VERSION 5.7 ;
BUSBITCHARS "[]" ;
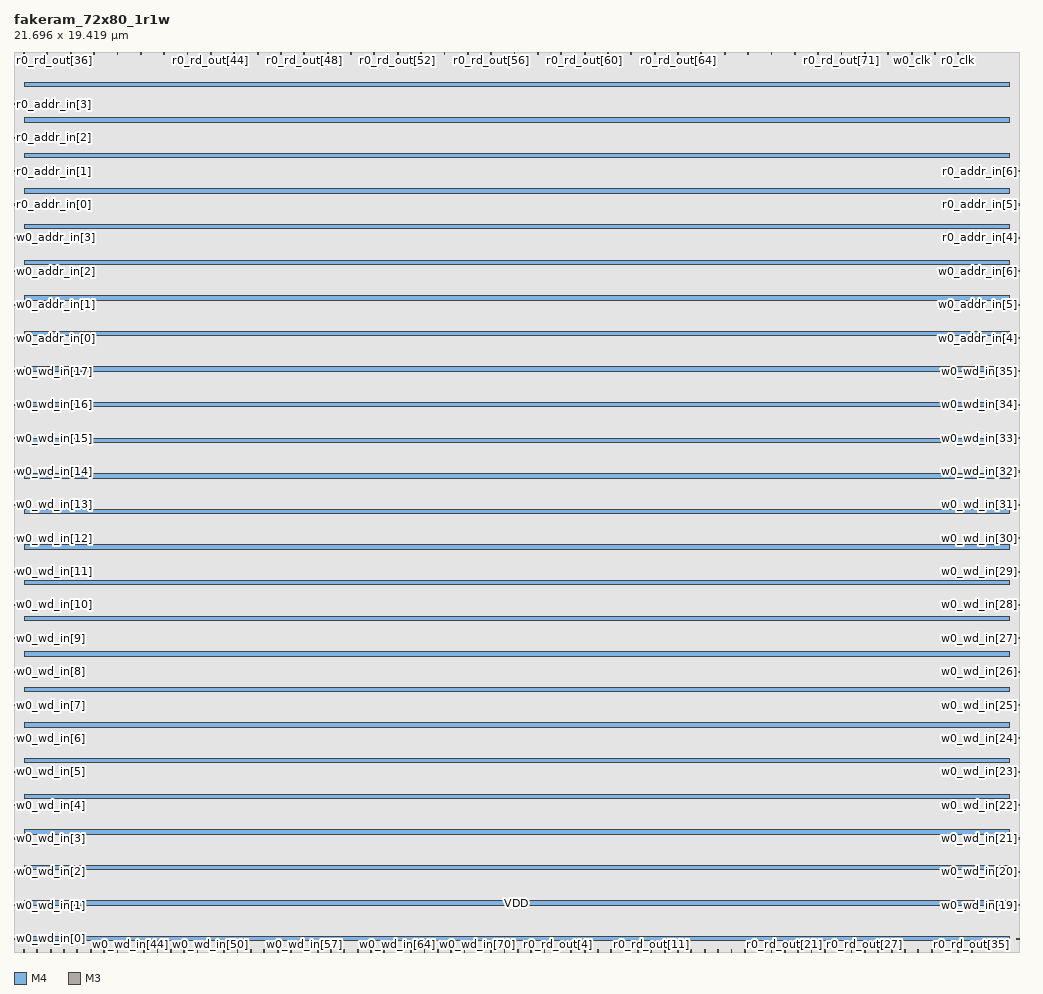
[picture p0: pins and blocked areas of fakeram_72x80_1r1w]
MACRO fakeram_72x80_1r1w
  FOREIGN fakeram_72x80_1r1w 0 0 ;
  SYMMETRY X Y R90 ;
  SIZE 21.696 BY 19.419 ;
  CLASS BLOCK ;
  PIN w0_wd_in[0]
    DIRECTION INPUT ;
    USE SIGNAL ;
    SHAPE ABUTMENT ;
    PORT
      LAYER M4 ;
      RECT 0.000 0.276 0.072 0.300 ;
    END
  END w0_wd_in[0]
  PIN w0_wd_in[1]
    DIRECTION INPUT ;
    USE SIGNAL ;
    SHAPE ABUTMENT ;
    PORT
      LAYER M4 ;
      RECT 0.000 0.996 0.072 1.020 ;
    END
  END w0_wd_in[1]
  PIN w0_wd_in[2]
    DIRECTION INPUT ;
    USE SIGNAL ;
    SHAPE ABUTMENT ;
    PORT
      LAYER M4 ;
      RECT 0.000 1.716 0.072 1.740 ;
    END
  END w0_wd_in[2]
  PIN w0_wd_in[3]
    DIRECTION INPUT ;
    USE SIGNAL ;
    SHAPE ABUTMENT ;
    PORT
      LAYER M4 ;
      RECT 0.000 2.436 0.072 2.460 ;
    END
  END w0_wd_in[3]
  PIN w0_wd_in[4]
    DIRECTION INPUT ;
    USE SIGNAL ;
    SHAPE ABUTMENT ;
    PORT
      LAYER M4 ;
      RECT 0.000 3.156 0.072 3.180 ;
    END
  END w0_wd_in[4]
  PIN w0_wd_in[5]
    DIRECTION INPUT ;
    USE SIGNAL ;
    SHAPE ABUTMENT ;
    PORT
      LAYER M4 ;
      RECT 0.000 3.876 0.072 3.900 ;
    END
  END w0_wd_in[5]
  PIN w0_wd_in[6]
    DIRECTION INPUT ;
    USE SIGNAL ;
    SHAPE ABUTMENT ;
    PORT
      LAYER M4 ;
      RECT 0.000 4.596 0.072 4.620 ;
    END
  END w0_wd_in[6]
  PIN w0_wd_in[7]
    DIRECTION INPUT ;
    USE SIGNAL ;
    SHAPE ABUTMENT ;
    PORT
      LAYER M4 ;
      RECT 0.000 5.316 0.072 5.340 ;
    END
  END w0_wd_in[7]
  PIN w0_wd_in[8]
    DIRECTION INPUT ;
    USE SIGNAL ;
    SHAPE ABUTMENT ;
    PORT
      LAYER M4 ;
      RECT 0.000 6.036 0.072 6.060 ;
    END
  END w0_wd_in[8]
  PIN w0_wd_in[9]
    DIRECTION INPUT ;
    USE SIGNAL ;
    SHAPE ABUTMENT ;
    PORT
      LAYER M4 ;
      RECT 0.000 6.756 0.072 6.780 ;
    END
  END w0_wd_in[9]
  PIN w0_wd_in[10]
    DIRECTION INPUT ;
    USE SIGNAL ;
    SHAPE ABUTMENT ;
    PORT
      LAYER M4 ;
      RECT 0.000 7.476 0.072 7.500 ;
    END
  END w0_wd_in[10]
  PIN w0_wd_in[11]
    DIRECTION INPUT ;
    USE SIGNAL ;
    SHAPE ABUTMENT ;
    PORT
      LAYER M4 ;
      RECT 0.000 8.196 0.072 8.220 ;
    END
  END w0_wd_in[11]
  PIN w0_wd_in[12]
    DIRECTION INPUT ;
    USE SIGNAL ;
    SHAPE ABUTMENT ;
    PORT
      LAYER M4 ;
      RECT 0.000 8.916 0.072 8.940 ;
    END
  END w0_wd_in[12]
  PIN w0_wd_in[13]
    DIRECTION INPUT ;
    USE SIGNAL ;
    SHAPE ABUTMENT ;
    PORT
      LAYER M4 ;
      RECT 0.000 9.636 0.072 9.660 ;
    END
  END w0_wd_in[13]
  PIN w0_wd_in[14]
    DIRECTION INPUT ;
    USE SIGNAL ;
    SHAPE ABUTMENT ;
    PORT
      LAYER M4 ;
      RECT 0.000 10.356 0.072 10.380 ;
    END
  END w0_wd_in[14]
  PIN w0_wd_in[15]
    DIRECTION INPUT ;
    USE SIGNAL ;
    SHAPE ABUTMENT ;
    PORT
      LAYER M4 ;
      RECT 0.000 11.076 0.072 11.100 ;
    END
  END w0_wd_in[15]
  PIN w0_wd_in[16]
    DIRECTION INPUT ;
    USE SIGNAL ;
    SHAPE ABUTMENT ;
    PORT
      LAYER M4 ;
      RECT 0.000 11.796 0.072 11.820 ;
    END
  END w0_wd_in[16]
  PIN w0_wd_in[17]
    DIRECTION INPUT ;
    USE SIGNAL ;
    SHAPE ABUTMENT ;
    PORT
      LAYER M4 ;
      RECT 0.000 12.516 0.072 12.540 ;
    END
  END w0_wd_in[17]
  PIN w0_wd_in[18]
    DIRECTION INPUT ;
    USE SIGNAL ;
    SHAPE ABUTMENT ;
    PORT
      LAYER M4 ;
      RECT 21.624 0.276 21.696 0.300 ;
    END
  END w0_wd_in[18]
  PIN w0_wd_in[19]
    DIRECTION INPUT ;
    USE SIGNAL ;
    SHAPE ABUTMENT ;
    PORT
      LAYER M4 ;
      RECT 21.624 0.996 21.696 1.020 ;
    END
  END w0_wd_in[19]
  PIN w0_wd_in[20]
    DIRECTION INPUT ;
    USE SIGNAL ;
    SHAPE ABUTMENT ;
    PORT
      LAYER M4 ;
      RECT 21.624 1.716 21.696 1.740 ;
    END
  END w0_wd_in[20]
  PIN w0_wd_in[21]
    DIRECTION INPUT ;
    USE SIGNAL ;
    SHAPE ABUTMENT ;
    PORT
      LAYER M4 ;
      RECT 21.624 2.436 21.696 2.460 ;
    END
  END w0_wd_in[21]
  PIN w0_wd_in[22]
    DIRECTION INPUT ;
    USE SIGNAL ;
    SHAPE ABUTMENT ;
    PORT
      LAYER M4 ;
      RECT 21.624 3.156 21.696 3.180 ;
    END
  END w0_wd_in[22]
  PIN w0_wd_in[23]
    DIRECTION INPUT ;
    USE SIGNAL ;
    SHAPE ABUTMENT ;
    PORT
      LAYER M4 ;
      RECT 21.624 3.876 21.696 3.900 ;
    END
  END w0_wd_in[23]
  PIN w0_wd_in[24]
    DIRECTION INPUT ;
    USE SIGNAL ;
    SHAPE ABUTMENT ;
    PORT
      LAYER M4 ;
      RECT 21.624 4.596 21.696 4.620 ;
    END
  END w0_wd_in[24]
  PIN w0_wd_in[25]
    DIRECTION INPUT ;
    USE SIGNAL ;
    SHAPE ABUTMENT ;
    PORT
      LAYER M4 ;
      RECT 21.624 5.316 21.696 5.340 ;
    END
  END w0_wd_in[25]
  PIN w0_wd_in[26]
    DIRECTION INPUT ;
    USE SIGNAL ;
    SHAPE ABUTMENT ;
    PORT
      LAYER M4 ;
      RECT 21.624 6.036 21.696 6.060 ;
    END
  END w0_wd_in[26]
  PIN w0_wd_in[27]
    DIRECTION INPUT ;
    USE SIGNAL ;
    SHAPE ABUTMENT ;
    PORT
      LAYER M4 ;
      RECT 21.624 6.756 21.696 6.780 ;
    END
  END w0_wd_in[27]
  PIN w0_wd_in[28]
    DIRECTION INPUT ;
    USE SIGNAL ;
    SHAPE ABUTMENT ;
    PORT
      LAYER M4 ;
      RECT 21.624 7.476 21.696 7.500 ;
    END
  END w0_wd_in[28]
  PIN w0_wd_in[29]
    DIRECTION INPUT ;
    USE SIGNAL ;
    SHAPE ABUTMENT ;
    PORT
      LAYER M4 ;
      RECT 21.624 8.196 21.696 8.220 ;
    END
  END w0_wd_in[29]
  PIN w0_wd_in[30]
    DIRECTION INPUT ;
    USE SIGNAL ;
    SHAPE ABUTMENT ;
    PORT
      LAYER M4 ;
      RECT 21.624 8.916 21.696 8.940 ;
    END
  END w0_wd_in[30]
  PIN w0_wd_in[31]
    DIRECTION INPUT ;
    USE SIGNAL ;
    SHAPE ABUTMENT ;
    PORT
      LAYER M4 ;
      RECT 21.624 9.636 21.696 9.660 ;
    END
  END w0_wd_in[31]
  PIN w0_wd_in[32]
    DIRECTION INPUT ;
    USE SIGNAL ;
    SHAPE ABUTMENT ;
    PORT
      LAYER M4 ;
      RECT 21.624 10.356 21.696 10.380 ;
    END
  END w0_wd_in[32]
  PIN w0_wd_in[33]
    DIRECTION INPUT ;
    USE SIGNAL ;
    SHAPE ABUTMENT ;
    PORT
      LAYER M4 ;
      RECT 21.624 11.076 21.696 11.100 ;
    END
  END w0_wd_in[33]
  PIN w0_wd_in[34]
    DIRECTION INPUT ;
    USE SIGNAL ;
    SHAPE ABUTMENT ;
    PORT
      LAYER M4 ;
      RECT 21.624 11.796 21.696 11.820 ;
    END
  END w0_wd_in[34]
  PIN w0_wd_in[35]
    DIRECTION INPUT ;
    USE SIGNAL ;
    SHAPE ABUTMENT ;
    PORT
      LAYER M4 ;
      RECT 21.624 12.516 21.696 12.540 ;
    END
  END w0_wd_in[35]
  PIN w0_wd_in[36]
    DIRECTION OUTPUT ;
    USE SIGNAL ;
    SHAPE ABUTMENT ;
    PORT
      LAYER M3 ;
      RECT 0.207 0.000 0.225 0.054 ;
    END
  END w0_wd_in[36]
  PIN w0_wd_in[37]
    DIRECTION OUTPUT ;
    USE SIGNAL ;
    SHAPE ABUTMENT ;
    PORT
      LAYER M3 ;
      RECT 0.495 0.000 0.513 0.054 ;
    END
  END w0_wd_in[37]
  PIN w0_wd_in[38]
    DIRECTION OUTPUT ;
    USE SIGNAL ;
    SHAPE ABUTMENT ;
    PORT
      LAYER M3 ;
      RECT 0.783 0.000 0.801 0.054 ;
    END
  END w0_wd_in[38]
  PIN w0_wd_in[39]
    DIRECTION OUTPUT ;
    USE SIGNAL ;
    SHAPE ABUTMENT ;
    PORT
      LAYER M3 ;
      RECT 1.071 0.000 1.089 0.054 ;
    END
  END w0_wd_in[39]
  PIN w0_wd_in[40]
    DIRECTION OUTPUT ;
    USE SIGNAL ;
    SHAPE ABUTMENT ;
    PORT
      LAYER M3 ;
      RECT 1.359 0.000 1.377 0.054 ;
    END
  END w0_wd_in[40]
  PIN w0_wd_in[41]
    DIRECTION OUTPUT ;
    USE SIGNAL ;
    SHAPE ABUTMENT ;
    PORT
      LAYER M3 ;
      RECT 1.647 0.000 1.665 0.054 ;
    END
  END w0_wd_in[41]
  PIN w0_wd_in[42]
    DIRECTION OUTPUT ;
    USE SIGNAL ;
    SHAPE ABUTMENT ;
    PORT
      LAYER M3 ;
      RECT 1.935 0.000 1.953 0.054 ;
    END
  END w0_wd_in[42]
  PIN w0_wd_in[43]
    DIRECTION OUTPUT ;
    USE SIGNAL ;
    SHAPE ABUTMENT ;
    PORT
      LAYER M3 ;
      RECT 2.223 0.000 2.241 0.054 ;
    END
  END w0_wd_in[43]
  PIN w0_wd_in[44]
    DIRECTION OUTPUT ;
    USE SIGNAL ;
    SHAPE ABUTMENT ;
    PORT
      LAYER M3 ;
      RECT 2.511 0.000 2.529 0.054 ;
    END
  END w0_wd_in[44]
  PIN w0_wd_in[45]
    DIRECTION OUTPUT ;
    USE SIGNAL ;
    SHAPE ABUTMENT ;
    PORT
      LAYER M3 ;
      RECT 2.799 0.000 2.817 0.054 ;
    END
  END w0_wd_in[45]
  PIN w0_wd_in[46]
    DIRECTION OUTPUT ;
    USE SIGNAL ;
    SHAPE ABUTMENT ;
    PORT
      LAYER M3 ;
      RECT 3.087 0.000 3.105 0.054 ;
    END
  END w0_wd_in[46]
  PIN w0_wd_in[47]
    DIRECTION OUTPUT ;
    USE SIGNAL ;
    SHAPE ABUTMENT ;
    PORT
      LAYER M3 ;
      RECT 3.375 0.000 3.393 0.054 ;
    END
  END w0_wd_in[47]
  PIN w0_wd_in[48]
    DIRECTION OUTPUT ;
    USE SIGNAL ;
    SHAPE ABUTMENT ;
    PORT
      LAYER M3 ;
      RECT 3.663 0.000 3.681 0.054 ;
    END
  END w0_wd_in[48]
  PIN w0_wd_in[49]
    DIRECTION OUTPUT ;
    USE SIGNAL ;
    SHAPE ABUTMENT ;
    PORT
      LAYER M3 ;
      RECT 3.951 0.000 3.969 0.054 ;
    END
  END w0_wd_in[49]
  PIN w0_wd_in[50]
    DIRECTION OUTPUT ;
    USE SIGNAL ;
    SHAPE ABUTMENT ;
    PORT
      LAYER M3 ;
      RECT 4.239 0.000 4.257 0.054 ;
    END
  END w0_wd_in[50]
  PIN w0_wd_in[51]
    DIRECTION OUTPUT ;
    USE SIGNAL ;
    SHAPE ABUTMENT ;
    PORT
      LAYER M3 ;
      RECT 4.527 0.000 4.545 0.054 ;
    END
  END w0_wd_in[51]
  PIN w0_wd_in[52]
    DIRECTION OUTPUT ;
    USE SIGNAL ;
    SHAPE ABUTMENT ;
    PORT
      LAYER M3 ;
      RECT 4.815 0.000 4.833 0.054 ;
    END
  END w0_wd_in[52]
  PIN w0_wd_in[53]
    DIRECTION OUTPUT ;
    USE SIGNAL ;
    SHAPE ABUTMENT ;
    PORT
      LAYER M3 ;
      RECT 5.103 0.000 5.121 0.054 ;
    END
  END w0_wd_in[53]
  PIN w0_wd_in[54]
    DIRECTION OUTPUT ;
    USE SIGNAL ;
    SHAPE ABUTMENT ;
    PORT
      LAYER M3 ;
      RECT 5.391 0.000 5.409 0.054 ;
    END
  END w0_wd_in[54]
  PIN w0_wd_in[55]
    DIRECTION OUTPUT ;
    USE SIGNAL ;
    SHAPE ABUTMENT ;
    PORT
      LAYER M3 ;
      RECT 5.679 0.000 5.697 0.054 ;
    END
  END w0_wd_in[55]
  PIN w0_wd_in[56]
    DIRECTION OUTPUT ;
    USE SIGNAL ;
    SHAPE ABUTMENT ;
    PORT
      LAYER M3 ;
      RECT 5.967 0.000 5.985 0.054 ;
    END
  END w0_wd_in[56]
  PIN w0_wd_in[57]
    DIRECTION OUTPUT ;
    USE SIGNAL ;
    SHAPE ABUTMENT ;
    PORT
      LAYER M3 ;
      RECT 6.255 0.000 6.273 0.054 ;
    END
  END w0_wd_in[57]
  PIN w0_wd_in[58]
    DIRECTION OUTPUT ;
    USE SIGNAL ;
    SHAPE ABUTMENT ;
    PORT
      LAYER M3 ;
      RECT 6.543 0.000 6.561 0.054 ;
    END
  END w0_wd_in[58]
  PIN w0_wd_in[59]
    DIRECTION OUTPUT ;
    USE SIGNAL ;
    SHAPE ABUTMENT ;
    PORT
      LAYER M3 ;
      RECT 6.831 0.000 6.849 0.054 ;
    END
  END w0_wd_in[59]
  PIN w0_wd_in[60]
    DIRECTION OUTPUT ;
    USE SIGNAL ;
    SHAPE ABUTMENT ;
    PORT
      LAYER M3 ;
      RECT 7.119 0.000 7.137 0.054 ;
    END
  END w0_wd_in[60]
  PIN w0_wd_in[61]
    DIRECTION OUTPUT ;
    USE SIGNAL ;
    SHAPE ABUTMENT ;
    PORT
      LAYER M3 ;
      RECT 7.407 0.000 7.425 0.054 ;
    END
  END w0_wd_in[61]
  PIN w0_wd_in[62]
    DIRECTION OUTPUT ;
    USE SIGNAL ;
    SHAPE ABUTMENT ;
    PORT
      LAYER M3 ;
      RECT 7.695 0.000 7.713 0.054 ;
    END
  END w0_wd_in[62]
  PIN w0_wd_in[63]
    DIRECTION OUTPUT ;
    USE SIGNAL ;
    SHAPE ABUTMENT ;
    PORT
      LAYER M3 ;
      RECT 7.983 0.000 8.001 0.054 ;
    END
  END w0_wd_in[63]
  PIN w0_wd_in[64]
    DIRECTION OUTPUT ;
    USE SIGNAL ;
    SHAPE ABUTMENT ;
    PORT
      LAYER M3 ;
      RECT 8.271 0.000 8.289 0.054 ;
    END
  END w0_wd_in[64]
  PIN w0_wd_in[65]
    DIRECTION OUTPUT ;
    USE SIGNAL ;
    SHAPE ABUTMENT ;
    PORT
      LAYER M3 ;
      RECT 8.559 0.000 8.577 0.054 ;
    END
  END w0_wd_in[65]
  PIN w0_wd_in[66]
    DIRECTION OUTPUT ;
    USE SIGNAL ;
    SHAPE ABUTMENT ;
    PORT
      LAYER M3 ;
      RECT 8.847 0.000 8.865 0.054 ;
    END
  END w0_wd_in[66]
  PIN w0_wd_in[67]
    DIRECTION OUTPUT ;
    USE SIGNAL ;
    SHAPE ABUTMENT ;
    PORT
      LAYER M3 ;
      RECT 9.135 0.000 9.153 0.054 ;
    END
  END w0_wd_in[67]
  PIN w0_wd_in[68]
    DIRECTION OUTPUT ;
    USE SIGNAL ;
    SHAPE ABUTMENT ;
    PORT
      LAYER M3 ;
      RECT 9.423 0.000 9.441 0.054 ;
    END
  END w0_wd_in[68]
  PIN w0_wd_in[69]
    DIRECTION OUTPUT ;
    USE SIGNAL ;
    SHAPE ABUTMENT ;
    PORT
      LAYER M3 ;
      RECT 9.711 0.000 9.729 0.054 ;
    END
  END w0_wd_in[69]
  PIN w0_wd_in[70]
    DIRECTION OUTPUT ;
    USE SIGNAL ;
    SHAPE ABUTMENT ;
    PORT
      LAYER M3 ;
      RECT 9.999 0.000 10.017 0.054 ;
    END
  END w0_wd_in[70]
  PIN w0_wd_in[71]
    DIRECTION OUTPUT ;
    USE SIGNAL ;
    SHAPE ABUTMENT ;
    PORT
      LAYER M3 ;
      RECT 10.287 0.000 10.305 0.054 ;
    END
  END w0_wd_in[71]
  PIN r0_rd_out[0]
    DIRECTION OUTPUT ;
    USE SIGNAL ;
    SHAPE ABUTMENT ;
    PORT
      LAYER M3 ;
      RECT 10.575 0.000 10.593 0.054 ;
    END
  END r0_rd_out[0]
  PIN r0_rd_out[1]
    DIRECTION OUTPUT ;
    USE SIGNAL ;
    SHAPE ABUTMENT ;
    PORT
      LAYER M3 ;
      RECT 10.863 0.000 10.881 0.054 ;
    END
  END r0_rd_out[1]
  PIN r0_rd_out[2]
    DIRECTION OUTPUT ;
    USE SIGNAL ;
    SHAPE ABUTMENT ;
    PORT
      LAYER M3 ;
      RECT 11.151 0.000 11.169 0.054 ;
    END
  END r0_rd_out[2]
  PIN r0_rd_out[3]
    DIRECTION OUTPUT ;
    USE SIGNAL ;
    SHAPE ABUTMENT ;
    PORT
      LAYER M3 ;
      RECT 11.439 0.000 11.457 0.054 ;
    END
  END r0_rd_out[3]
  PIN r0_rd_out[4]
    DIRECTION OUTPUT ;
    USE SIGNAL ;
    SHAPE ABUTMENT ;
    PORT
      LAYER M3 ;
      RECT 11.727 0.000 11.745 0.054 ;
    END
  END r0_rd_out[4]
  PIN r0_rd_out[5]
    DIRECTION OUTPUT ;
    USE SIGNAL ;
    SHAPE ABUTMENT ;
    PORT
      LAYER M3 ;
      RECT 12.015 0.000 12.033 0.054 ;
    END
  END r0_rd_out[5]
  PIN r0_rd_out[6]
    DIRECTION OUTPUT ;
    USE SIGNAL ;
    SHAPE ABUTMENT ;
    PORT
      LAYER M3 ;
      RECT 12.303 0.000 12.321 0.054 ;
    END
  END r0_rd_out[6]
  PIN r0_rd_out[7]
    DIRECTION OUTPUT ;
    USE SIGNAL ;
    SHAPE ABUTMENT ;
    PORT
      LAYER M3 ;
      RECT 12.591 0.000 12.609 0.054 ;
    END
  END r0_rd_out[7]
  PIN r0_rd_out[8]
    DIRECTION OUTPUT ;
    USE SIGNAL ;
    SHAPE ABUTMENT ;
    PORT
      LAYER M3 ;
      RECT 12.879 0.000 12.897 0.054 ;
    END
  END r0_rd_out[8]
  PIN r0_rd_out[9]
    DIRECTION OUTPUT ;
    USE SIGNAL ;
    SHAPE ABUTMENT ;
    PORT
      LAYER M3 ;
      RECT 13.167 0.000 13.185 0.054 ;
    END
  END r0_rd_out[9]
  PIN r0_rd_out[10]
    DIRECTION OUTPUT ;
    USE SIGNAL ;
    SHAPE ABUTMENT ;
    PORT
      LAYER M3 ;
      RECT 13.455 0.000 13.473 0.054 ;
    END
  END r0_rd_out[10]
  PIN r0_rd_out[11]
    DIRECTION OUTPUT ;
    USE SIGNAL ;
    SHAPE ABUTMENT ;
    PORT
      LAYER M3 ;
      RECT 13.743 0.000 13.761 0.054 ;
    END
  END r0_rd_out[11]
  PIN r0_rd_out[12]
    DIRECTION OUTPUT ;
    USE SIGNAL ;
    SHAPE ABUTMENT ;
    PORT
      LAYER M3 ;
      RECT 14.031 0.000 14.049 0.054 ;
    END
  END r0_rd_out[12]
  PIN r0_rd_out[13]
    DIRECTION OUTPUT ;
    USE SIGNAL ;
    SHAPE ABUTMENT ;
    PORT
      LAYER M3 ;
      RECT 14.319 0.000 14.337 0.054 ;
    END
  END r0_rd_out[13]
  PIN r0_rd_out[14]
    DIRECTION OUTPUT ;
    USE SIGNAL ;
    SHAPE ABUTMENT ;
    PORT
      LAYER M3 ;
      RECT 14.607 0.000 14.625 0.054 ;
    END
  END r0_rd_out[14]
  PIN r0_rd_out[15]
    DIRECTION OUTPUT ;
    USE SIGNAL ;
    SHAPE ABUTMENT ;
    PORT
      LAYER M3 ;
      RECT 14.895 0.000 14.913 0.054 ;
    END
  END r0_rd_out[15]
  PIN r0_rd_out[16]
    DIRECTION OUTPUT ;
    USE SIGNAL ;
    SHAPE ABUTMENT ;
    PORT
      LAYER M3 ;
      RECT 15.183 0.000 15.201 0.054 ;
    END
  END r0_rd_out[16]
  PIN r0_rd_out[17]
    DIRECTION OUTPUT ;
    USE SIGNAL ;
    SHAPE ABUTMENT ;
    PORT
      LAYER M3 ;
      RECT 15.471 0.000 15.489 0.054 ;
    END
  END r0_rd_out[17]
  PIN r0_rd_out[18]
    DIRECTION OUTPUT ;
    USE SIGNAL ;
    SHAPE ABUTMENT ;
    PORT
      LAYER M3 ;
      RECT 15.759 0.000 15.777 0.054 ;
    END
  END r0_rd_out[18]
  PIN r0_rd_out[19]
    DIRECTION OUTPUT ;
    USE SIGNAL ;
    SHAPE ABUTMENT ;
    PORT
      LAYER M3 ;
      RECT 16.047 0.000 16.065 0.054 ;
    END
  END r0_rd_out[19]
  PIN r0_rd_out[20]
    DIRECTION OUTPUT ;
    USE SIGNAL ;
    SHAPE ABUTMENT ;
    PORT
      LAYER M3 ;
      RECT 16.335 0.000 16.353 0.054 ;
    END
  END r0_rd_out[20]
  PIN r0_rd_out[21]
    DIRECTION OUTPUT ;
    USE SIGNAL ;
    SHAPE ABUTMENT ;
    PORT
      LAYER M3 ;
      RECT 16.623 0.000 16.641 0.054 ;
    END
  END r0_rd_out[21]
  PIN r0_rd_out[22]
    DIRECTION OUTPUT ;
    USE SIGNAL ;
    SHAPE ABUTMENT ;
    PORT
      LAYER M3 ;
      RECT 16.911 0.000 16.929 0.054 ;
    END
  END r0_rd_out[22]
  PIN r0_rd_out[23]
    DIRECTION OUTPUT ;
    USE SIGNAL ;
    SHAPE ABUTMENT ;
    PORT
      LAYER M3 ;
      RECT 17.199 0.000 17.217 0.054 ;
    END
  END r0_rd_out[23]
  PIN r0_rd_out[24]
    DIRECTION OUTPUT ;
    USE SIGNAL ;
    SHAPE ABUTMENT ;
    PORT
      LAYER M3 ;
      RECT 17.487 0.000 17.505 0.054 ;
    END
  END r0_rd_out[24]
  PIN r0_rd_out[25]
    DIRECTION OUTPUT ;
    USE SIGNAL ;
    SHAPE ABUTMENT ;
    PORT
      LAYER M3 ;
      RECT 17.775 0.000 17.793 0.054 ;
    END
  END r0_rd_out[25]
  PIN r0_rd_out[26]
    DIRECTION OUTPUT ;
    USE SIGNAL ;
    SHAPE ABUTMENT ;
    PORT
      LAYER M3 ;
      RECT 18.063 0.000 18.081 0.054 ;
    END
  END r0_rd_out[26]
  PIN r0_rd_out[27]
    DIRECTION OUTPUT ;
    USE SIGNAL ;
    SHAPE ABUTMENT ;
    PORT
      LAYER M3 ;
      RECT 18.351 0.000 18.369 0.054 ;
    END
  END r0_rd_out[27]
  PIN r0_rd_out[28]
    DIRECTION OUTPUT ;
    USE SIGNAL ;
    SHAPE ABUTMENT ;
    PORT
      LAYER M3 ;
      RECT 18.639 0.000 18.657 0.054 ;
    END
  END r0_rd_out[28]
  PIN r0_rd_out[29]
    DIRECTION OUTPUT ;
    USE SIGNAL ;
    SHAPE ABUTMENT ;
    PORT
      LAYER M3 ;
      RECT 18.927 0.000 18.945 0.054 ;
    END
  END r0_rd_out[29]
  PIN r0_rd_out[30]
    DIRECTION OUTPUT ;
    USE SIGNAL ;
    SHAPE ABUTMENT ;
    PORT
      LAYER M3 ;
      RECT 19.215 0.000 19.233 0.054 ;
    END
  END r0_rd_out[30]
  PIN r0_rd_out[31]
    DIRECTION OUTPUT ;
    USE SIGNAL ;
    SHAPE ABUTMENT ;
    PORT
      LAYER M3 ;
      RECT 19.503 0.000 19.521 0.054 ;
    END
  END r0_rd_out[31]
  PIN r0_rd_out[32]
    DIRECTION OUTPUT ;
    USE SIGNAL ;
    SHAPE ABUTMENT ;
    PORT
      LAYER M3 ;
      RECT 19.791 0.000 19.809 0.054 ;
    END
  END r0_rd_out[32]
  PIN r0_rd_out[33]
    DIRECTION OUTPUT ;
    USE SIGNAL ;
    SHAPE ABUTMENT ;
    PORT
      LAYER M3 ;
      RECT 20.079 0.000 20.097 0.054 ;
    END
  END r0_rd_out[33]
  PIN r0_rd_out[34]
    DIRECTION OUTPUT ;
    USE SIGNAL ;
    SHAPE ABUTMENT ;
    PORT
      LAYER M3 ;
      RECT 20.367 0.000 20.385 0.054 ;
    END
  END r0_rd_out[34]
  PIN r0_rd_out[35]
    DIRECTION OUTPUT ;
    USE SIGNAL ;
    SHAPE ABUTMENT ;
    PORT
      LAYER M3 ;
      RECT 20.655 0.000 20.673 0.054 ;
    END
  END r0_rd_out[35]
  PIN r0_rd_out[36]
    DIRECTION OUTPUT ;
    USE SIGNAL ;
    SHAPE ABUTMENT ;
    PORT
      LAYER M3 ;
      RECT 0.207 19.365 0.225 19.419 ;
    END
  END r0_rd_out[36]
  PIN r0_rd_out[37]
    DIRECTION OUTPUT ;
    USE SIGNAL ;
    SHAPE ABUTMENT ;
    PORT
      LAYER M3 ;
      RECT 0.711 19.365 0.729 19.419 ;
    END
  END r0_rd_out[37]
  PIN r0_rd_out[38]
    DIRECTION OUTPUT ;
    USE SIGNAL ;
    SHAPE ABUTMENT ;
    PORT
      LAYER M3 ;
      RECT 1.215 19.365 1.233 19.419 ;
    END
  END r0_rd_out[38]
  PIN r0_rd_out[39]
    DIRECTION OUTPUT ;
    USE SIGNAL ;
    SHAPE ABUTMENT ;
    PORT
      LAYER M3 ;
      RECT 1.719 19.365 1.737 19.419 ;
    END
  END r0_rd_out[39]
  PIN r0_rd_out[40]
    DIRECTION OUTPUT ;
    USE SIGNAL ;
    SHAPE ABUTMENT ;
    PORT
      LAYER M3 ;
      RECT 2.223 19.365 2.241 19.419 ;
    END
  END r0_rd_out[40]
  PIN r0_rd_out[41]
    DIRECTION OUTPUT ;
    USE SIGNAL ;
    SHAPE ABUTMENT ;
    PORT
      LAYER M3 ;
      RECT 2.727 19.365 2.745 19.419 ;
    END
  END r0_rd_out[41]
  PIN r0_rd_out[42]
    DIRECTION OUTPUT ;
    USE SIGNAL ;
    SHAPE ABUTMENT ;
    PORT
      LAYER M3 ;
      RECT 3.231 19.365 3.249 19.419 ;
    END
  END r0_rd_out[42]
  PIN r0_rd_out[43]
    DIRECTION OUTPUT ;
    USE SIGNAL ;
    SHAPE ABUTMENT ;
    PORT
      LAYER M3 ;
      RECT 3.735 19.365 3.753 19.419 ;
    END
  END r0_rd_out[43]
  PIN r0_rd_out[44]
    DIRECTION OUTPUT ;
    USE SIGNAL ;
    SHAPE ABUTMENT ;
    PORT
      LAYER M3 ;
      RECT 4.239 19.365 4.257 19.419 ;
    END
  END r0_rd_out[44]
  PIN r0_rd_out[45]
    DIRECTION OUTPUT ;
    USE SIGNAL ;
    SHAPE ABUTMENT ;
    PORT
      LAYER M3 ;
      RECT 4.743 19.365 4.761 19.419 ;
    END
  END r0_rd_out[45]
  PIN r0_rd_out[46]
    DIRECTION OUTPUT ;
    USE SIGNAL ;
    SHAPE ABUTMENT ;
    PORT
      LAYER M3 ;
      RECT 5.247 19.365 5.265 19.419 ;
    END
  END r0_rd_out[46]
  PIN r0_rd_out[47]
    DIRECTION OUTPUT ;
    USE SIGNAL ;
    SHAPE ABUTMENT ;
    PORT
      LAYER M3 ;
      RECT 5.751 19.365 5.769 19.419 ;
    END
  END r0_rd_out[47]
  PIN r0_rd_out[48]
    DIRECTION OUTPUT ;
    USE SIGNAL ;
    SHAPE ABUTMENT ;
    PORT
      LAYER M3 ;
      RECT 6.255 19.365 6.273 19.419 ;
    END
  END r0_rd_out[48]
  PIN r0_rd_out[49]
    DIRECTION OUTPUT ;
    USE SIGNAL ;
    SHAPE ABUTMENT ;
    PORT
      LAYER M3 ;
      RECT 6.759 19.365 6.777 19.419 ;
    END
  END r0_rd_out[49]
  PIN r0_rd_out[50]
    DIRECTION OUTPUT ;
    USE SIGNAL ;
    SHAPE ABUTMENT ;
    PORT
      LAYER M3 ;
      RECT 7.263 19.365 7.281 19.419 ;
    END
  END r0_rd_out[50]
  PIN r0_rd_out[51]
    DIRECTION OUTPUT ;
    USE SIGNAL ;
    SHAPE ABUTMENT ;
    PORT
      LAYER M3 ;
      RECT 7.767 19.365 7.785 19.419 ;
    END
  END r0_rd_out[51]
  PIN r0_rd_out[52]
    DIRECTION OUTPUT ;
    USE SIGNAL ;
    SHAPE ABUTMENT ;
    PORT
      LAYER M3 ;
      RECT 8.271 19.365 8.289 19.419 ;
    END
  END r0_rd_out[52]
  PIN r0_rd_out[53]
    DIRECTION OUTPUT ;
    USE SIGNAL ;
    SHAPE ABUTMENT ;
    PORT
      LAYER M3 ;
      RECT 8.775 19.365 8.793 19.419 ;
    END
  END r0_rd_out[53]
  PIN r0_rd_out[54]
    DIRECTION OUTPUT ;
    USE SIGNAL ;
    SHAPE ABUTMENT ;
    PORT
      LAYER M3 ;
      RECT 9.279 19.365 9.297 19.419 ;
    END
  END r0_rd_out[54]
  PIN r0_rd_out[55]
    DIRECTION OUTPUT ;
    USE SIGNAL ;
    SHAPE ABUTMENT ;
    PORT
      LAYER M3 ;
      RECT 9.783 19.365 9.801 19.419 ;
    END
  END r0_rd_out[55]
  PIN r0_rd_out[56]
    DIRECTION OUTPUT ;
    USE SIGNAL ;
    SHAPE ABUTMENT ;
    PORT
      LAYER M3 ;
      RECT 10.287 19.365 10.305 19.419 ;
    END
  END r0_rd_out[56]
  PIN r0_rd_out[57]
    DIRECTION OUTPUT ;
    USE SIGNAL ;
    SHAPE ABUTMENT ;
    PORT
      LAYER M3 ;
      RECT 10.791 19.365 10.809 19.419 ;
    END
  END r0_rd_out[57]
  PIN r0_rd_out[58]
    DIRECTION OUTPUT ;
    USE SIGNAL ;
    SHAPE ABUTMENT ;
    PORT
      LAYER M3 ;
      RECT 11.295 19.365 11.313 19.419 ;
    END
  END r0_rd_out[58]
  PIN r0_rd_out[59]
    DIRECTION OUTPUT ;
    USE SIGNAL ;
    SHAPE ABUTMENT ;
    PORT
      LAYER M3 ;
      RECT 11.799 19.365 11.817 19.419 ;
    END
  END r0_rd_out[59]
  PIN r0_rd_out[60]
    DIRECTION OUTPUT ;
    USE SIGNAL ;
    SHAPE ABUTMENT ;
    PORT
      LAYER M3 ;
      RECT 12.303 19.365 12.321 19.419 ;
    END
  END r0_rd_out[60]
  PIN r0_rd_out[61]
    DIRECTION OUTPUT ;
    USE SIGNAL ;
    SHAPE ABUTMENT ;
    PORT
      LAYER M3 ;
      RECT 12.807 19.365 12.825 19.419 ;
    END
  END r0_rd_out[61]
  PIN r0_rd_out[62]
    DIRECTION OUTPUT ;
    USE SIGNAL ;
    SHAPE ABUTMENT ;
    PORT
      LAYER M3 ;
      RECT 13.311 19.365 13.329 19.419 ;
    END
  END r0_rd_out[62]
  PIN r0_rd_out[63]
    DIRECTION OUTPUT ;
    USE SIGNAL ;
    SHAPE ABUTMENT ;
    PORT
      LAYER M3 ;
      RECT 13.815 19.365 13.833 19.419 ;
    END
  END r0_rd_out[63]
  PIN r0_rd_out[64]
    DIRECTION OUTPUT ;
    USE SIGNAL ;
    SHAPE ABUTMENT ;
    PORT
      LAYER M3 ;
      RECT 14.319 19.365 14.337 19.419 ;
    END
  END r0_rd_out[64]
  PIN r0_rd_out[65]
    DIRECTION OUTPUT ;
    USE SIGNAL ;
    SHAPE ABUTMENT ;
    PORT
      LAYER M3 ;
      RECT 14.823 19.365 14.841 19.419 ;
    END
  END r0_rd_out[65]
  PIN r0_rd_out[66]
    DIRECTION OUTPUT ;
    USE SIGNAL ;
    SHAPE ABUTMENT ;
    PORT
      LAYER M3 ;
      RECT 15.327 19.365 15.345 19.419 ;
    END
  END r0_rd_out[66]
  PIN r0_rd_out[67]
    DIRECTION OUTPUT ;
    USE SIGNAL ;
    SHAPE ABUTMENT ;
    PORT
      LAYER M3 ;
      RECT 15.831 19.365 15.849 19.419 ;
    END
  END r0_rd_out[67]
  PIN r0_rd_out[68]
    DIRECTION OUTPUT ;
    USE SIGNAL ;
    SHAPE ABUTMENT ;
    PORT
      LAYER M3 ;
      RECT 16.335 19.365 16.353 19.419 ;
    END
  END r0_rd_out[68]
  PIN r0_rd_out[69]
    DIRECTION OUTPUT ;
    USE SIGNAL ;
    SHAPE ABUTMENT ;
    PORT
      LAYER M3 ;
      RECT 16.839 19.365 16.857 19.419 ;
    END
  END r0_rd_out[69]
  PIN r0_rd_out[70]
    DIRECTION OUTPUT ;
    USE SIGNAL ;
    SHAPE ABUTMENT ;
    PORT
      LAYER M3 ;
      RECT 17.343 19.365 17.361 19.419 ;
    END
  END r0_rd_out[70]
  PIN r0_rd_out[71]
    DIRECTION OUTPUT ;
    USE SIGNAL ;
    SHAPE ABUTMENT ;
    PORT
      LAYER M3 ;
      RECT 17.847 19.365 17.865 19.419 ;
    END
  END r0_rd_out[71]
  PIN w0_addr_in[0]
    DIRECTION INPUT ;
    USE SIGNAL ;
    SHAPE ABUTMENT ;
    PORT
      LAYER M4 ;
      RECT 0.000 13.236 0.072 13.260 ;
    END
  END w0_addr_in[0]
  PIN w0_addr_in[1]
    DIRECTION INPUT ;
    USE SIGNAL ;
    SHAPE ABUTMENT ;
    PORT
      LAYER M4 ;
      RECT 0.000 13.956 0.072 13.980 ;
    END
  END w0_addr_in[1]
  PIN w0_addr_in[2]
    DIRECTION INPUT ;
    USE SIGNAL ;
    SHAPE ABUTMENT ;
    PORT
      LAYER M4 ;
      RECT 0.000 14.676 0.072 14.700 ;
    END
  END w0_addr_in[2]
  PIN w0_addr_in[3]
    DIRECTION INPUT ;
    USE SIGNAL ;
    SHAPE ABUTMENT ;
    PORT
      LAYER M4 ;
      RECT 0.000 15.396 0.072 15.420 ;
    END
  END w0_addr_in[3]
  PIN w0_addr_in[4]
    DIRECTION INPUT ;
    USE SIGNAL ;
    SHAPE ABUTMENT ;
    PORT
      LAYER M4 ;
      RECT 21.624 13.236 21.696 13.260 ;
    END
  END w0_addr_in[4]
  PIN w0_addr_in[5]
    DIRECTION INPUT ;
    USE SIGNAL ;
    SHAPE ABUTMENT ;
    PORT
      LAYER M4 ;
      RECT 21.624 13.956 21.696 13.980 ;
    END
  END w0_addr_in[5]
  PIN w0_addr_in[6]
    DIRECTION INPUT ;
    USE SIGNAL ;
    SHAPE ABUTMENT ;
    PORT
      LAYER M4 ;
      RECT 21.624 14.676 21.696 14.700 ;
    END
  END w0_addr_in[6]
  PIN r0_addr_in[0]
    DIRECTION INPUT ;
    USE SIGNAL ;
    SHAPE ABUTMENT ;
    PORT
      LAYER M4 ;
      RECT 0.000 16.116 0.072 16.140 ;
    END
  END r0_addr_in[0]
  PIN r0_addr_in[1]
    DIRECTION INPUT ;
    USE SIGNAL ;
    SHAPE ABUTMENT ;
    PORT
      LAYER M4 ;
      RECT 0.000 16.836 0.072 16.860 ;
    END
  END r0_addr_in[1]
  PIN r0_addr_in[2]
    DIRECTION INPUT ;
    USE SIGNAL ;
    SHAPE ABUTMENT ;
    PORT
      LAYER M4 ;
      RECT 0.000 17.556 0.072 17.580 ;
    END
  END r0_addr_in[2]
  PIN r0_addr_in[3]
    DIRECTION INPUT ;
    USE SIGNAL ;
    SHAPE ABUTMENT ;
    PORT
      LAYER M4 ;
      RECT 0.000 18.276 0.072 18.300 ;
    END
  END r0_addr_in[3]
  PIN r0_addr_in[4]
    DIRECTION INPUT ;
    USE SIGNAL ;
    SHAPE ABUTMENT ;
    PORT
      LAYER M4 ;
      RECT 21.624 15.396 21.696 15.420 ;
    END
  END r0_addr_in[4]
  PIN r0_addr_in[5]
    DIRECTION INPUT ;
    USE SIGNAL ;
    SHAPE ABUTMENT ;
    PORT
      LAYER M4 ;
      RECT 21.624 16.116 21.696 16.140 ;
    END
  END r0_addr_in[5]
  PIN r0_addr_in[6]
    DIRECTION INPUT ;
    USE SIGNAL ;
    SHAPE ABUTMENT ;
    PORT
      LAYER M4 ;
      RECT 21.624 16.836 21.696 16.860 ;
    END
  END r0_addr_in[6]
  PIN w0_we_in
    DIRECTION INPUT ;
    USE SIGNAL ;
    SHAPE ABUTMENT ;
    PORT
      LAYER M3 ;
      RECT 18.351 19.365 18.369 19.419 ;
    END
  END w0_we_in
  PIN w0_ce_in
    DIRECTION INPUT ;
    USE SIGNAL ;
    SHAPE ABUTMENT ;
    PORT
      LAYER M3 ;
      RECT 18.855 19.365 18.873 19.419 ;
    END
  END w0_ce_in
  PIN w0_clk
    DIRECTION INPUT ;
    USE SIGNAL ;
    SHAPE ABUTMENT ;
    PORT
      LAYER M3 ;
      RECT 19.359 19.365 19.377 19.419 ;
    END
  END w0_clk
  PIN r0_ce_in
    DIRECTION INPUT ;
    USE SIGNAL ;
    SHAPE ABUTMENT ;
    PORT
      LAYER M3 ;
      RECT 19.863 19.365 19.881 19.419 ;
    END
  END r0_ce_in
  PIN r0_clk
    DIRECTION INPUT ;
    USE SIGNAL ;
    SHAPE ABUTMENT ;
    PORT
      LAYER M3 ;
      RECT 20.367 19.365 20.385 19.419 ;
    END
  END r0_clk
  PIN VSS
    DIRECTION INOUT ;
    USE GROUND ;
    PORT
      LAYER M4 ;
      RECT 0.216 0.240 21.480 0.336 ;
      RECT 0.216 1.008 21.480 1.104 ;
      RECT 0.216 1.776 21.480 1.872 ;
      RECT 0.216 2.544 21.480 2.640 ;
      RECT 0.216 3.312 21.480 3.408 ;
      RECT 0.216 4.080 21.480 4.176 ;
      RECT 0.216 4.848 21.480 4.944 ;
      RECT 0.216 5.616 21.480 5.712 ;
      RECT 0.216 6.384 21.480 6.480 ;
      RECT 0.216 7.152 21.480 7.248 ;
      RECT 0.216 7.920 21.480 8.016 ;
      RECT 0.216 8.688 21.480 8.784 ;
      RECT 0.216 9.456 21.480 9.552 ;
      RECT 0.216 10.224 21.480 10.320 ;
      RECT 0.216 10.992 21.480 11.088 ;
      RECT 0.216 11.760 21.480 11.856 ;
      RECT 0.216 12.528 21.480 12.624 ;
      RECT 0.216 13.296 21.480 13.392 ;
      RECT 0.216 14.064 21.480 14.160 ;
      RECT 0.216 14.832 21.480 14.928 ;
      RECT 0.216 15.600 21.480 15.696 ;
      RECT 0.216 16.368 21.480 16.464 ;
      RECT 0.216 17.136 21.480 17.232 ;
      RECT 0.216 17.904 21.480 18.000 ;
      RECT 0.216 18.672 21.480 18.768 ;
    END
  END VSS
  PIN VDD
    DIRECTION INOUT ;
    USE POWER ;
    PORT
      LAYER M4 ;
      RECT 0.216 0.240 21.480 0.336 ;
      RECT 0.216 1.008 21.480 1.104 ;
      RECT 0.216 1.776 21.480 1.872 ;
      RECT 0.216 2.544 21.480 2.640 ;
      RECT 0.216 3.312 21.480 3.408 ;
      RECT 0.216 4.080 21.480 4.176 ;
      RECT 0.216 4.848 21.480 4.944 ;
      RECT 0.216 5.616 21.480 5.712 ;
      RECT 0.216 6.384 21.480 6.480 ;
      RECT 0.216 7.152 21.480 7.248 ;
      RECT 0.216 7.920 21.480 8.016 ;
      RECT 0.216 8.688 21.480 8.784 ;
      RECT 0.216 9.456 21.480 9.552 ;
      RECT 0.216 10.224 21.480 10.320 ;
      RECT 0.216 10.992 21.480 11.088 ;
      RECT 0.216 11.760 21.480 11.856 ;
      RECT 0.216 12.528 21.480 12.624 ;
      RECT 0.216 13.296 21.480 13.392 ;
      RECT 0.216 14.064 21.480 14.160 ;
      RECT 0.216 14.832 21.480 14.928 ;
      RECT 0.216 15.600 21.480 15.696 ;
      RECT 0.216 16.368 21.480 16.464 ;
      RECT 0.216 17.136 21.480 17.232 ;
      RECT 0.216 17.904 21.480 18.000 ;
      RECT 0.216 18.672 21.480 18.768 ;
    END
  END VDD
  OBS
    LAYER M1 ;
    RECT 0 0 21.696 19.419 ;
    LAYER M2 ;
    RECT 0 0 21.696 19.419 ;
    LAYER M3 ;
    RECT 0 0 21.696 19.419 ;
    LAYER M4 ;
    RECT 0 0 21.696 19.419 ;
  END
END fakeram_72x80_1r1w

END LIBRARY
